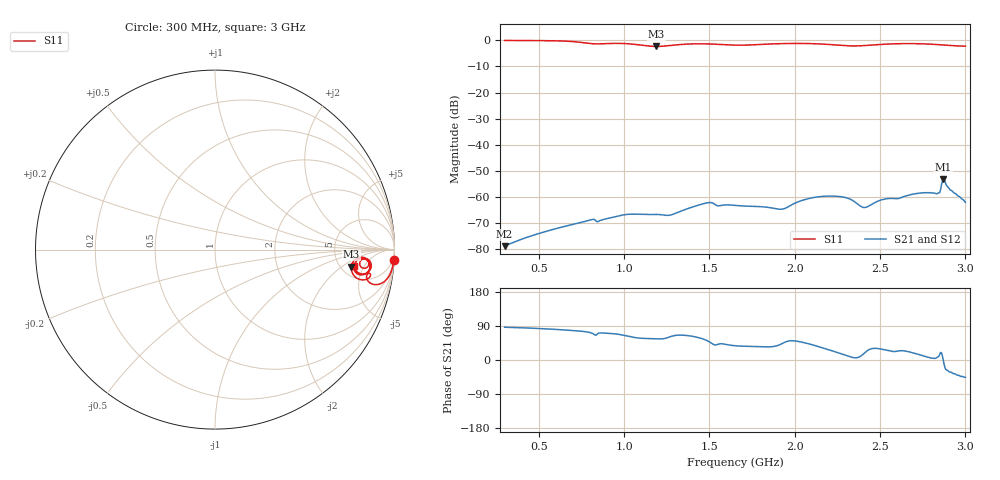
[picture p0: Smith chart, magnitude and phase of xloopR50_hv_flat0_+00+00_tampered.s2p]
! xloopR50_hv_flat0_+00+00_tampered, gap C 0.80 pF
! simulated by sim/fixtures_fdtd.py (S12 = S21, S22 not computed)
# HZ S RI R 50
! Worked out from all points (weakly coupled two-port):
!   541 points, 300 MHz to 3 GHz, reference 50 ohm
!   highest |S21| = -53.29 dB at 2.87 GHz (marker M1); lowest = -79.0 dB at 300 MHz (marker M2)
!   lowest |S11| = -2.3 dB at 1.19 GHz (marker M3), VSWR 7.54, Z = 310 - j142 ohm
!   |S11| at or under -10 dB: nowhere
!   |S22| runs from - to - dB; largest |S21 - S12| = 0
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3e8  0.9963 -0.0606  6.9e-06 0.000112  6.9e-06 0.000112  0 0
6e8  0.9704 -0.1465  3.92e-05 0.000241  3.92e-05 0.000241  0 0
7.5e8  0.893 -0.1952  7.8e-05 0.000313  7.8e-05 0.000313  0 0
8.85e8  0.856 -0.1323  0.00012 0.00035  0.00012 0.00035  0 0
1.015e9  0.8505 -0.1626  0.000204 0.000409  0.000204 0.000409  0 0
1.1e9  0.7958 -0.1621  0.000247 0.000386  0.000247 0.000386  0 0
1.19e9  0.7599 -0.095  0.000256 0.000379  0.000256 0.000379  0 0
1.2e9  0.7617 -0.0861  0.000257 0.000377  0.000257 0.000377  0 0
1.275e9  0.8008 -0.0444  0.000209 0.000396  0.000209 0.000396  0 0
1.495e9  0.8506 -0.0958  0.000505 0.000582  0.000505 0.000582  0 0
1.55e9  0.8348 -0.1041  0.000501 0.000444  0.000501 0.000444  0 0
1.65e9  0.8073 -0.0861  0.00054 0.000416  0.00054 0.000416  0 0
1.925e9  0.866 -0.0695  0.00042 0.000394  0.00042 0.000394  0 0
2.1e9  0.8591 -0.1195  0.000722 0.000617  0.000722 0.000617  0 0
2.285e9  0.7874 -0.1191  0.000952 0.000247  0.000952 0.000247  0 0
2.41e9  0.7946 -0.0574  0.000587 0.000203  0.000587 0.000203  0 0
2.55e9  0.8504 -0.0619  0.000842 0.000385  0.000842 0.000385  0 0
2.74e9  0.8529 -0.1229  0.00115 0.000261  0.00115 0.000261  0 0
2.84e9  0.8187 -0.141  0.00116 0.000173  0.00116 0.000173  0 0
2.87e9  0.8052 -0.1401  0.00217 1.39e-05  0.00217 1.39e-05  0 0
2.915e9  0.7866 -0.1303  0.00112 -0.000704  0.00112 -0.000704  0 0
3e9  0.7719 -0.0938  0.000546 -0.000558  0.000546 -0.000558  0 0
